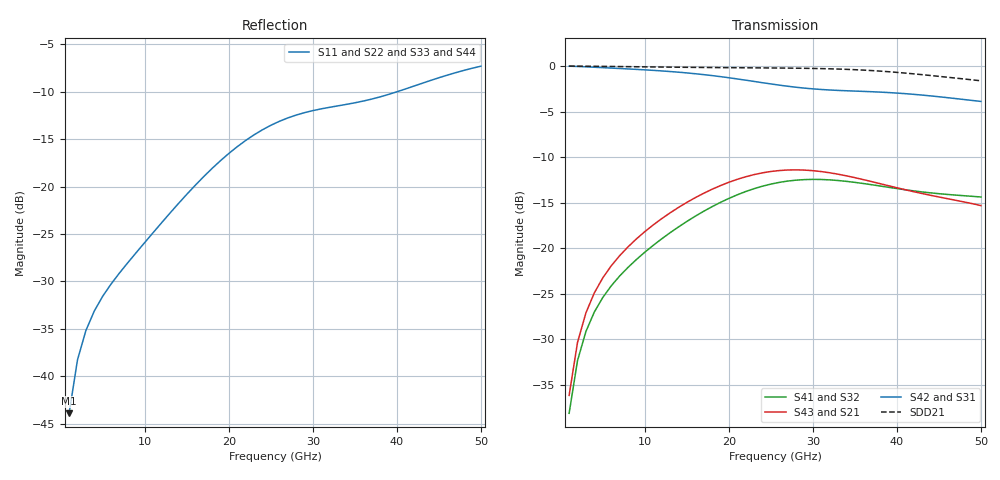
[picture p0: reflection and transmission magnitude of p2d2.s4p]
! Impedora 0.10.0 via model, case p2d2 (fullwave/cases.json), 2026-11-19
! Differential pair, one plane pair, two stitching vias, lossy dielectric: ports in the antipads.
! Ports: 1, 2 = via A, B on the upper layer; 3, 4 = via A, B on the lower layer, 50 ohm each.
! Compared with the fine 3D mesh.
# Hz S RI R 50
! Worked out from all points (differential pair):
!   50 points, 1 GHz to 50 GHz, reference 50 ohm
!   strongest paths, dB at 1 GHz, 13 GHz, 26 GHz, 38 GHz, 50 GHz:
!     S42: 0.0, -0.6, -2.1, -2.9, -3.9
!     S31: 0.0, -0.6, -2.1, -2.9, -3.9
!     S43: -36.1, -16.1, -11.5, -12.9, -15.3
!     S21: -36.1, -16.1, -11.5, -12.9, -15.3
!     S41: -38.1, -18.3, -12.8, -13.2, -14.4
!     S32: -38.1, -18.3, -12.8, -13.2, -14.4
!   taken as a pair (ports 2,1 in; 4,3 out), SDD21 dB: 0.0, -0.1, -0.2, -0.6, -1.6
!   lowest |S11| = -43.9 dB at 1 GHz (marker M1), VSWR 1.01, Z = 50.1 + j0.632 ohm
!   |S11| at or under -10 dB: start of sweep to 40 GHz
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1e9  0.000881 0.00631  0.00198 0.0155  0.9962 -0.0652  -0.00173 -0.0123
     0.00198 0.0155  0.000881 0.00631  -0.00173 -0.0123  0.9962 -0.0652
     0.9962 -0.0652  -0.00173 -0.0123  0.000881 0.00631  0.00198 0.0155
     -0.00173 -0.0123  0.9962 -0.0652  0.00198 0.0155  0.000881 0.00631
3e9  0.00918 0.0148  0.0152 0.0415  0.9717 -0.19  -0.0134 -0.0323
     0.0152 0.0415  0.00918 0.0148  -0.0134 -0.0323  0.9717 -0.19
     0.9717 -0.19  -0.0134 -0.0323  0.00918 0.0148  0.0152 0.0415
     -0.0134 -0.0323  0.9717 -0.19  0.0152 0.0415  0.00918 0.0148
5e9  0.0203 0.0169  0.0347 0.0593  0.9312 -0.3047  -0.03 -0.0445
     0.0347 0.0593  0.0203 0.0169  -0.03 -0.0445  0.9312 -0.3047
     0.9312 -0.3047  -0.03 -0.0445  0.0203 0.0169  0.0347 0.0593
     -0.03 -0.0445  0.9312 -0.3047  0.0347 0.0593  0.0203 0.0169
1.8e10  0.117 -0.0425  0.21 0.0175  0.4038 -0.7892  -0.1689 0.00745
        0.21 0.0175  0.117 -0.0425  -0.1689 0.00745  0.4038 -0.7892
        0.4038 -0.7892  -0.1689 0.00745  0.117 -0.0425  0.21 0.0175
        -0.1689 0.00745  0.4038 -0.7892  0.21 0.0175  0.117 -0.0425
2.5e10  0.1371 -0.1597  0.2243 -0.1391  0.0749 -0.7942  -0.1664 0.1515
        0.2243 -0.1391  0.1371 -0.1597  -0.1664 0.1515  0.0749 -0.7942
        0.0749 -0.7942  -0.1664 0.1515  0.1371 -0.1597  0.2243 -0.1391
        -0.1664 0.1515  0.0749 -0.7942  0.2243 -0.1391  0.1371 -0.1597
3.2e10  0.0773 -0.2503  0.0953 -0.2416  -0.1628 -0.7207  -0.0292 0.2356
        0.0953 -0.2416  0.0773 -0.2503  -0.0292 0.2356  -0.1628 -0.7207
        -0.1628 -0.7207  -0.0292 0.2356  0.0773 -0.2503  0.0953 -0.2416
        -0.0292 0.2356  -0.1628 -0.7207  0.0953 -0.2416  0.0773 -0.2503
5e10  -0.0981 -0.4204  -0.1258 -0.1167  -0.5732 -0.2839  0.1793 0.0664
      -0.1258 -0.1167  -0.0981 -0.4204  0.1793 0.0664  -0.5732 -0.2839
      -0.5732 -0.2839  0.1793 0.0664  -0.0981 -0.4204  -0.1258 -0.1167
      0.1793 0.0664  -0.5732 -0.2839  -0.1258 -0.1167  -0.0981 -0.4204
